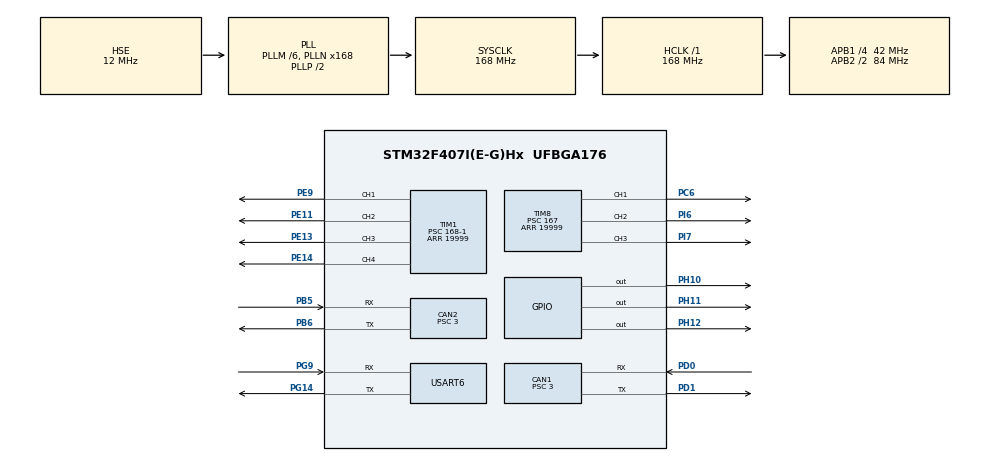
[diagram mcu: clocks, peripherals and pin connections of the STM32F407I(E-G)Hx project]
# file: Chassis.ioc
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CAN1.BS1=CAN_BS1_10TQ
CAN1.BS2=CAN_BS2_3TQ
CAN1.CalculateBaudRate=1000000
CAN1.CalculateTimeBit=1000
CAN1.CalculateTimeQuantum=71.42857142857143
CAN1.Prescaler=3
CAN2.BS1=CAN_BS1_10TQ
CAN2.BS2=CAN_BS2_3TQ
CAN2.CalculateBaudRate=1000000
CAN2.CalculateTimeBit=1000
CAN2.CalculateTimeQuantum=71.42857142857143
CAN2.Prescaler=3
Dma.Request0=USART6_RX
Dma.Request1=USART6_TX
Dma.USART6_RX.0.Direction=DMA_PERIPH_TO_MEMORY
Dma.USART6_RX.0.FIFOMode=DMA_FIFOMODE_DISABLE
Dma.USART6_RX.0.Instance=DMA2_Stream1
Dma.USART6_RX.0.MemDataAlignment=DMA_MDATAALIGN_BYTE
Dma.USART6_RX.0.MemInc=DMA_MINC_ENABLE
Dma.USART6_RX.0.Mode=DMA_NORMAL
Dma.USART6_RX.0.PeriphDataAlignment=DMA_PDATAALIGN_BYTE
Dma.USART6_RX.0.PeriphInc=DMA_PINC_DISABLE
Dma.USART6_RX.0.Priority=DMA_PRIORITY_HIGH
Dma.USART6_TX.1.Direction=DMA_MEMORY_TO_PERIPH
Dma.USART6_TX.1.FIFOMode=DMA_FIFOMODE_DISABLE
Dma.USART6_TX.1.Instance=DMA2_Stream6
Dma.USART6_TX.1.MemDataAlignment=DMA_MDATAALIGN_BYTE
Dma.USART6_TX.1.MemInc=DMA_MINC_ENABLE
Dma.USART6_TX.1.Mode=DMA_NORMAL
Dma.USART6_TX.1.PeriphDataAlignment=DMA_PDATAALIGN_BYTE
Dma.USART6_TX.1.PeriphInc=DMA_PINC_DISABLE
Dma.USART6_TX.1.Priority=DMA_PRIORITY_HIGH
Mcu.Family=STM32F4
Mcu.Name=STM32F407I(E-G)Hx
Mcu.Package=UFBGA176
NVIC.CAN1_RX0_IRQn=true\:0\:0\:false\:false\:true\:true\:true\:true
NVIC.CAN1_TX_IRQn=true\:0\:0\:false\:false\:true\:true\:true\:true
NVIC.CAN2_RX0_IRQn=true\:0\:0\:false\:false\:true\:true\:true\:true
NVIC.CAN2_TX_IRQn=true\:0\:0\:false\:false\:true\:true\:true\:true
NVIC.DMA2_Stream1_IRQn=true\:0\:0\:false\:false\:true\:false\:true\:true
NVIC.DMA2_Stream6_IRQn=true\:0\:0\:false\:false\:true\:false\:true\:true
NVIC.PriorityGroup=NVIC_PRIORITYGROUP_4
NVIC.USART6_IRQn=true\:0\:0\:false\:false\:true\:true\:true\:true
PA13.Mode=Serial_Wire
PA13.Signal=SYS_JTMS-SWDIO
PA14.Mode=Serial_Wire
PA14.Signal=SYS_JTCK-SWCLK
PB5.Mode=CAN_Activate
PB5.Signal=CAN2_RX
PB6.Mode=CAN_Activate
PB6.Signal=CAN2_TX
PC6.Signal=S_TIM8_CH1
PD0.Mode=CAN_Activate
PD0.Signal=CAN1_RX
PD1.Mode=CAN_Activate
PD1.Signal=CAN1_TX
PE11.Signal=S_TIM1_CH2
PE13.Signal=S_TIM1_CH3
PE14.Signal=S_TIM1_CH4
PE9.Signal=S_TIM1_CH1
PG14.Mode=Asynchronous
PG14.Signal=USART6_TX
PG9.Mode=Asynchronous
PG9.Signal=USART6_RX
PH0-OSC_IN.Mode=HSE-External-Oscillator
PH0-OSC_IN.Signal=RCC_OSC_IN
PH1-OSC_OUT.Mode=HSE-External-Oscillator
PH1-OSC_OUT.Signal=RCC_OSC_OUT
PH10.PinState=GPIO_PIN_SET
PH10.Signal=GPIO_Output
PH11.PinState=GPIO_PIN_SET
PH11.Signal=GPIO_Output
PH12.PinState=GPIO_PIN_SET
PH12.Signal=GPIO_Output
PI6.Signal=S_TIM8_CH2
PI7.Signal=S_TIM8_CH3
ProjectManager.HeapSize=0x200
ProjectManager.StackSize=0x400
ProjectManager.TargetToolchain=MDK-ARM V5.32
RCC.48MHZClocksFreq_Value=84000000
RCC.AHBFreq_Value=168000000
RCC.APB1CLKDivider=RCC_HCLK_DIV4
RCC.APB1Freq_Value=42000000
RCC.APB1TimFreq_Value=84000000
RCC.APB2CLKDivider=RCC_HCLK_DIV2
RCC.APB2Freq_Value=84000000
RCC.APB2TimFreq_Value=168000000
RCC.CortexFreq_Value=168000000
RCC.HCLKFreq_Value=168000000
RCC.HSE_VALUE=12000000
RCC.HSI_VALUE=16000000
RCC.LSE_VALUE=32768
RCC.PLLM=6
RCC.PLLN=168
RCC.PLLSourceVirtual=RCC_PLLSOURCE_HSE
RCC.SYSCLKFreq_VALUE=168000000
RCC.SYSCLKSource=RCC_SYSCLKSOURCE_PLLCLK
RCC.VCOOutputFreq_Value=336000000
SH.S_TIM1_CH1.0=TIM1_CH1,PWM Generation1 CH1
SH.S_TIM1_CH2.0=TIM1_CH2,PWM Generation2 CH2
SH.S_TIM1_CH3.0=TIM1_CH3,PWM Generation3 CH3
SH.S_TIM1_CH4.0=TIM1_CH4,PWM Generation4 CH4
SH.S_TIM8_CH1.0=TIM8_CH1,PWM Generation1 CH1
SH.S_TIM8_CH2.0=TIM8_CH2,PWM Generation2 CH2
SH.S_TIM8_CH3.0=TIM8_CH3,PWM Generation3 CH3
STMicroelectronics.X-CUBE-ALGOBUILD.1.4.0.LibraryCcDSPOoLibraryJjDSPOoLibrary=true
STMicroelectronics.X-CUBE-AZRTOS-F4.1.1.0.TX_DISABLE_PREEMPTION_THRESHOLD=1
STMicroelectronics.X-CUBE-AZRTOS-F4.1.1.0.TX_DISABLE_REDUNDANT_CLEARING=1
STMicroelectronics.X-CUBE-AZRTOS-F4.1.1.0.TX_DISABLE_STACK_FILLING=1
STMicroelectronics.X-CUBE-AZRTOS-F4.1.1.0.TX_INLINE_THREAD_RESUME_SUSPEND=1
STMicroelectronics.X-CUBE-AZRTOS-F4.1.1.0.TX_NOT_INTERRUPTABLE=1
STMicroelectronics.X-CUBE-AZRTOS-F4.1.1.0.TX_REACTIVATE_INLINE=1
STMicroelectronics.X-CUBE-AZRTOS-F4.1.1.0.TX_TIMER_PROCESS_IN_ISR=1
STMicroelectronics.X-CUBE-AZRTOS-F4.1.1.0_IsAnAzureRtosMw=true
TIM1.Channel-PWM\ Generation1\ CH1=TIM_CHANNEL_1
TIM1.Channel-PWM\ Generation2\ CH2=TIM_CHANNEL_2
TIM1.Channel-PWM\ Generation3\ CH3=TIM_CHANNEL_3
TIM1.Channel-PWM\ Generation4\ CH4=TIM_CHANNEL_4
TIM1.Period=19999
TIM1.Prescaler=168-1
TIM1.Pulse-PWM\ Generation1\ CH1=0
TIM1.Pulse-PWM\ Generation2\ CH2=0
TIM1.Pulse-PWM\ Generation3\ CH3=0
TIM8.Channel-PWM\ Generation1\ CH1=TIM_CHANNEL_1
TIM8.Channel-PWM\ Generation2\ CH2=TIM_CHANNEL_2
TIM8.Channel-PWM\ Generation3\ CH3=TIM_CHANNEL_3
TIM8.Period=19999
TIM8.Prescaler=167
TIM8.Pulse-PWM\ Generation1\ CH1=0
USART6.VirtualMode=VM_ASYNC
VP_IWDG_VS_IWDG.Mode=IWDG_Activate
VP_STMicroelectronics.X-CUBE-ALGOBUILD_VS_DSPOoLibraryJjLibrary_1.4.0_1.4.0.Mode=DSPOoLibraryJjLibrary
VP_TIM1_VS_ClockSourceINT.Mode=Internal
VP_TIM8_VS_ClockSourceINT.Mode=Internal
board=custom

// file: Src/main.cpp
/* USER CODE BEGIN Header */
/**
  ******************************************************************************
  * @file           : main.c
  * @brief          : Main program body
  ******************************************************************************
  * @attention
  *
  * Copyright (c) 2025 STMicroelectronics.
  * All rights reserved.
  *
  * This software is licensed under terms that can be found in the LICENSE file
  * in the root directory of this software component.
  * If no LICENSE file comes with this software, it is provided AS-IS.
  *
  ******************************************************************************
  */
/* USER CODE END Header */
#include "main.h"

/* USER CODE BEGIN Includes */
#include "bsp.hpp"

#include "DJIMotorHandler.hpp"
#include "ChassisController.hpp"
#include "LED.hpp"
#include "MaixComm.hpp"
#include "SteeringGear.hpp"

#include "stm32f4xx_it.h"
/* USER CODE END Includes */

CAN_HandleTypeDef hcan1;
CAN_HandleTypeDef hcan2;

TIM_HandleTypeDef htim1;
TIM_HandleTypeDef htim8;

UART_HandleTypeDef huart6;
DMA_HandleTypeDef hdma_usart6_rx;
DMA_HandleTypeDef hdma_usart6_tx;

/* USER CODE BEGIN PV */
DJIMotorHandler *DJImotorHandler = DJIMotorHandler::Instance();
ChassisController *chassisController = ChassisController::Instance();
MaixComm *maixcomm = MaixComm::Instance();
SteeringGear *steeringgear = SteeringGear::Instance();
/* USER CODE END PV */

void SystemClock_Config(void);
static void MX_GPIO_Init(void);
static void MX_DMA_Init(void);
static void MX_CAN1_Init(void);
static void MX_CAN2_Init(void);
static void MX_USART6_UART_Init(void);
static void MX_TIM1_Init(void);
static void MX_TIM8_Init(void);
/* USER CODE BEGIN PFP */
void EnableSystickIT(void);
/* USER CODE END PFP */

/* USER CODE BEGIN 0 */

void EnableSystickIT(void)
{
  uint32_t tick_ms = 1; // 1

  HAL_SYSTICK_CLKSourceConfig(SYSTICK_CLKSOURCE_HCLK_DIV8);

  uint32_t reload = SystemCoreClock / 8000 * tick_ms; // SystemCoreClock / 8000 * tick_ms;

  SysTick->CTRL |= SysTick_CTRL_TICKINT_Msk; // Enable SysTick Interrupt
  SysTick->LOAD = reload;
  SysTick->CTRL |= SysTick_CTRL_ENABLE_Msk; // Enable SysTick
}

void SysTick_Handler(void)
{
  /* USER CODE BEGIN SysTick_IRQn 0 */

  /* USER CODE END SysTick_IRQn 0 */
  HAL_IncTick();
  /* USER CODE BEGIN SysTick_IRQn 1 */
  // receive and update data

  // Run control loop
	maixcomm->Update();
  chassisController->Run();
//  steeringgear->SetAngle(45,1);
//  steeringgear->SetAngle(40,3);
  // send data
  DJImotorHandler->sendControlData();

  /* USER CODE END SysTick_IRQn 1 */
}

/* USER CODE END 0 */

int main(void)
{

  /* MCU Configuration--------------------------------------------------------*/

  /* Reset of all peripherals, Initializes the Flash interface and the Systick. */
  HAL_Init();

  /* Configure the system clock */
  SystemClock_Config();

  /* Initialize all configured peripherals */
  MX_GPIO_Init();
  MX_DMA_Init();
  MX_CAN1_Init();
  MX_CAN2_Init();
  MX_USART6_UART_Init();
  MX_TIM1_Init();
  MX_TIM8_Init();
  /* USER CODE BEGIN 2 */
  bsp_init();
	maixcomm->Init();
  chassisController->Init();
  steeringgear->Init();
//	DJImotorHandler->sendControlData();

  EnableSystickIT();
  LED_ALL_ON();
  /* USER CODE END 2 */

  /* Infinite loop */
  while (1)
  {

  }
}

void SystemClock_Config(void)
{
  RCC_OscInitTypeDef RCC_OscInitStruct = {0};
  RCC_ClkInitTypeDef RCC_ClkInitStruct = {0};

  /** Configure the main internal regulator output voltage
  */
  __HAL_RCC_PWR_CLK_ENABLE();
  __HAL_PWR_VOLTAGESCALING_CONFIG(PWR_REGULATOR_VOLTAGE_SCALE1);

  /** Initializes the RCC Oscillators according to the specified parameters
  * in the RCC_OscInitTypeDef structure.
  */
  RCC_OscInitStruct.OscillatorType = RCC_OSCILLATORTYPE_HSE;
  RCC_OscInitStruct.HSEState = RCC_HSE_ON;
  RCC_OscInitStruct.PLL.PLLState = RCC_PLL_ON;
  RCC_OscInitStruct.PLL.PLLSource = RCC_PLLSOURCE_HSE;
  RCC_OscInitStruct.PLL.PLLM = 6;
  RCC_OscInitStruct.PLL.PLLN = 168;
  RCC_OscInitStruct.PLL.PLLP = RCC_PLLP_DIV2;
  RCC_OscInitStruct.PLL.PLLQ = 4;
  if (HAL_RCC_OscConfig(&RCC_OscInitStruct) != HAL_OK)
  {
    Error_Handler();
  }

  /** Initializes the CPU, AHB and APB buses clocks
  */
  RCC_ClkInitStruct.ClockType = RCC_CLOCKTYPE_HCLK|RCC_CLOCKTYPE_SYSCLK
                              |RCC_CLOCKTYPE_PCLK1|RCC_CLOCKTYPE_PCLK2;
  RCC_ClkInitStruct.SYSCLKSource = RCC_SYSCLKSOURCE_PLLCLK;
  RCC_ClkInitStruct.AHBCLKDivider = RCC_SYSCLK_DIV1;
  RCC_ClkInitStruct.APB1CLKDivider = RCC_HCLK_DIV4;
  RCC_ClkInitStruct.APB2CLKDivider = RCC_HCLK_DIV2;

  if (HAL_RCC_ClockConfig(&RCC_ClkInitStruct, FLASH_LATENCY_5) != HAL_OK)
  {
    Error_Handler();
  }
}

static void MX_CAN1_Init(void)
{

  hcan1.Instance = CAN1;
  hcan1.Init.Prescaler = 3;
  hcan1.Init.Mode = CAN_MODE_NORMAL;
  hcan1.Init.SyncJumpWidth = CAN_SJW_1TQ;
  hcan1.Init.TimeSeg1 = CAN_BS1_10TQ;
  hcan1.Init.TimeSeg2 = CAN_BS2_3TQ;
  hcan1.Init.TimeTriggeredMode = DISABLE;
  hcan1.Init.AutoBusOff = DISABLE;
  hcan1.Init.AutoWakeUp = DISABLE;
  hcan1.Init.AutoRetransmission = DISABLE;
  hcan1.Init.ReceiveFifoLocked = DISABLE;
  hcan1.Init.TransmitFifoPriority = DISABLE;
  if (HAL_CAN_Init(&hcan1) != HAL_OK)
  {
    Error_Handler();
  }

}

static void MX_CAN2_Init(void)
{

  hcan2.Instance = CAN2;
  hcan2.Init.Prescaler = 3;
  hcan2.Init.Mode = CAN_MODE_NORMAL;
  hcan2.Init.SyncJumpWidth = CAN_SJW_1TQ;
  hcan2.Init.TimeSeg1 = CAN_BS1_10TQ;
  hcan2.Init.TimeSeg2 = CAN_BS2_3TQ;
  hcan2.Init.TimeTriggeredMode = DISABLE;
  hcan2.Init.AutoBusOff = DISABLE;
  hcan2.Init.AutoWakeUp = DISABLE;
  hcan2.Init.AutoRetransmission = DISABLE;
  hcan2.Init.ReceiveFifoLocked = DISABLE;
  hcan2.Init.TransmitFifoPriority = DISABLE;
  if (HAL_CAN_Init(&hcan2) != HAL_OK)
  {
    Error_Handler();
  }

}

static void MX_TIM1_Init(void)
{

  TIM_ClockConfigTypeDef sClockSourceConfig = {0};
  TIM_MasterConfigTypeDef sMasterConfig = {0};
  TIM_OC_InitTypeDef sConfigOC = {0};
  TIM_BreakDeadTimeConfigTypeDef sBreakDeadTimeConfig = {0};

  htim1.Instance = TIM1;
  htim1.Init.Prescaler = 168-1;
  htim1.Init.CounterMode = TIM_COUNTERMODE_UP;
  htim1.Init.Period = 19999;
  htim1.Init.ClockDivision = TIM_CLOCKDIVISION_DIV1;
  htim1.Init.RepetitionCounter = 0;
  htim1.Init.AutoReloadPreload = TIM_AUTORELOAD_PRELOAD_DISABLE;
  if (HAL_TIM_Base_Init(&htim1) != HAL_OK)
  {
    Error_Handler();
  }
  sClockSourceConfig.ClockSource = TIM_CLOCKSOURCE_INTERNAL;
  if (HAL_TIM_ConfigClockSource(&htim1, &sClockSourceConfig) != HAL_OK)
  {
    Error_Handler();
  }
  if (HAL_TIM_PWM_Init(&htim1) != HAL_OK)
  {
    Error_Handler();
  }
  sMasterConfig.MasterOutputTrigger = TIM_TRGO_RESET;
  sMasterConfig.MasterSlaveMode = TIM_MASTERSLAVEMODE_DISABLE;
  if (HAL_TIMEx_MasterConfigSynchronization(&htim1, &sMasterConfig) != HAL_OK)
  {
    Error_Handler();
  }
  sConfigOC.OCMode = TIM_OCMODE_PWM1;
  sConfigOC.Pulse = 0;
  sConfigOC.OCPolarity = TIM_OCPOLARITY_HIGH;
  sConfigOC.OCNPolarity = TIM_OCNPOLARITY_HIGH;
  sConfigOC.OCFastMode = TIM_OCFAST_DISABLE;
  sConfigOC.OCIdleState = TIM_OCIDLESTATE_RESET;
  sConfigOC.OCNIdleState = TIM_OCNIDLESTATE_RESET;
  if (HAL_TIM_PWM_ConfigChannel(&htim1, &sConfigOC, TIM_CHANNEL_1) != HAL_OK)
  {
    Error_Handler();
  }
  if (HAL_TIM_PWM_ConfigChannel(&htim1, &sConfigOC, TIM_CHANNEL_2) != HAL_OK)
  {
    Error_Handler();
  }
  if (HAL_TIM_PWM_ConfigChannel(&htim1, &sConfigOC, TIM_CHANNEL_3) != HAL_OK)
  {
    Error_Handler();
  }
  if (HAL_TIM_PWM_ConfigChannel(&htim1, &sConfigOC, TIM_CHANNEL_4) != HAL_OK)
  {
    Error_Handler();
  }
  sBreakDeadTimeConfig.OffStateRunMode = TIM_OSSR_DISABLE;
  sBreakDeadTimeConfig.OffStateIDLEMode = TIM_OSSI_DISABLE;
  sBreakDeadTimeConfig.LockLevel = TIM_LOCKLEVEL_OFF;
  sBreakDeadTimeConfig.DeadTime = 0;
  sBreakDeadTimeConfig.BreakState = TIM_BREAK_DISABLE;
  sBreakDeadTimeConfig.BreakPolarity = TIM_BREAKPOLARITY_HIGH;
  sBreakDeadTimeConfig.AutomaticOutput = TIM_AUTOMATICOUTPUT_DISABLE;
  if (HAL_TIMEx_ConfigBreakDeadTime(&htim1, &sBreakDeadTimeConfig) != HAL_OK)
  {
    Error_Handler();
  }
  HAL_TIM_MspPostInit(&htim1);

}

static void MX_TIM8_Init(void)
{

  TIM_ClockConfigTypeDef sClockSourceConfig = {0};
  TIM_MasterConfigTypeDef sMasterConfig = {0};
  TIM_OC_InitTypeDef sConfigOC = {0};
  TIM_BreakDeadTimeConfigTypeDef sBreakDeadTimeConfig = {0};

  htim8.Instance = TIM8;
  htim8.Init.Prescaler = 167;
  htim8.Init.CounterMode = TIM_COUNTERMODE_UP;
  htim8.Init.Period = 19999;
  htim8.Init.ClockDivision = TIM_CLOCKDIVISION_DIV1;
  htim8.Init.RepetitionCounter = 0;
  htim8.Init.AutoReloadPreload = TIM_AUTORELOAD_PRELOAD_DISABLE;
  if (HAL_TIM_Base_Init(&htim8) != HAL_OK)
  {
    Error_Handler();
  }
  sClockSourceConfig.ClockSource = TIM_CLOCKSOURCE_INTERNAL;
  if (HAL_TIM_ConfigClockSource(&htim8, &sClockSourceConfig) != HAL_OK)
  {
    Error_Handler();
  }
  if (HAL_TIM_PWM_Init(&htim8) != HAL_OK)
  {
    Error_Handler();
  }
  sMasterConfig.MasterOutputTrigger = TIM_TRGO_RESET;
  sMasterConfig.MasterSlaveMode = TIM_MASTERSLAVEMODE_DISABLE;
  if (HAL_TIMEx_MasterConfigSynchronization(&htim8, &sMasterConfig) != HAL_OK)
  {
    Error_Handler();
  }
  sConfigOC.OCMode = TIM_OCMODE_PWM1;
  sConfigOC.Pulse = 0;
  sConfigOC.OCPolarity = TIM_OCPOLARITY_HIGH;
  sConfigOC.OCNPolarity = TIM_OCNPOLARITY_HIGH;
  sConfigOC.OCFastMode = TIM_OCFAST_DISABLE;
  sConfigOC.OCIdleState = TIM_OCIDLESTATE_RESET;
  sConfigOC.OCNIdleState = TIM_OCNIDLESTATE_RESET;
  if (HAL_TIM_PWM_ConfigChannel(&htim8, &sConfigOC, TIM_CHANNEL_1) != HAL_OK)
  {
    Error_Handler();
  }
  if (HAL_TIM_PWM_ConfigChannel(&htim8, &sConfigOC, TIM_CHANNEL_2) != HAL_OK)
  {
    Error_Handler();
  }
  if (HAL_TIM_PWM_ConfigChannel(&htim8, &sConfigOC, TIM_CHANNEL_3) != HAL_OK)
  {
    Error_Handler();
  }
  sBreakDeadTimeConfig.OffStateRunMode = TIM_OSSR_DISABLE;
  sBreakDeadTimeConfig.OffStateIDLEMode = TIM_OSSI_DISABLE;
  sBreakDeadTimeConfig.LockLevel = TIM_LOCKLEVEL_OFF;
  sBreakDeadTimeConfig.DeadTime = 0;
  sBreakDeadTimeConfig.BreakState = TIM_BREAK_DISABLE;
  sBreakDeadTimeConfig.BreakPolarity = TIM_BREAKPOLARITY_HIGH;
  sBreakDeadTimeConfig.AutomaticOutput = TIM_AUTOMATICOUTPUT_DISABLE;
  if (HAL_TIMEx_ConfigBreakDeadTime(&htim8, &sBreakDeadTimeConfig) != HAL_OK)
  {
    Error_Handler();
  }
  HAL_TIM_MspPostInit(&htim8);

}

static void MX_USART6_UART_Init(void)
{

  huart6.Instance = USART6;
  huart6.Init.BaudRate = 115200;
  huart6.Init.WordLength = UART_WORDLENGTH_8B;
  huart6.Init.StopBits = UART_STOPBITS_1;
  huart6.Init.Parity = UART_PARITY_NONE;
  huart6.Init.Mode = UART_MODE_TX_RX;
  huart6.Init.HwFlowCtl = UART_HWCONTROL_NONE;
  huart6.Init.OverSampling = UART_OVERSAMPLING_16;
  if (HAL_UART_Init(&huart6) != HAL_OK)
  {
    Error_Handler();
  }

}

static void MX_DMA_Init(void)
{

  /* DMA controller clock enable */
  __HAL_RCC_DMA2_CLK_ENABLE();

  /* DMA interrupt init */
  /* DMA2_Stream1_IRQn interrupt configuration */
  HAL_NVIC_SetPriority(DMA2_Stream1_IRQn, 0, 0);
  HAL_NVIC_EnableIRQ(DMA2_Stream1_IRQn);
  /* DMA2_Stream6_IRQn interrupt configuration */
  HAL_NVIC_SetPriority(DMA2_Stream6_IRQn, 0, 0);
  HAL_NVIC_EnableIRQ(DMA2_Stream6_IRQn);

}

static void MX_GPIO_Init(void)
{
  GPIO_InitTypeDef GPIO_InitStruct = {0};

  /* GPIO Ports Clock Enable */
  __HAL_RCC_GPIOB_CLK_ENABLE();
  __HAL_RCC_GPIOG_CLK_ENABLE();
  __HAL_RCC_GPIOA_CLK_ENABLE();
  __HAL_RCC_GPIOD_CLK_ENABLE();
  __HAL_RCC_GPIOH_CLK_ENABLE();
  __HAL_RCC_GPIOF_CLK_ENABLE();

  /*Configure GPIO pin Output Level */
  HAL_GPIO_WritePin(GPIOH, GPIO_PIN_12|GPIO_PIN_11|GPIO_PIN_10, GPIO_PIN_SET);

  /*Configure GPIO pin : PF6 */
  GPIO_InitStruct.Pin = GPIO_PIN_6;
  GPIO_InitStruct.Mode = GPIO_MODE_AF_PP;
  GPIO_InitStruct.Pull = GPIO_NOPULL;
  GPIO_InitStruct.Speed = GPIO_SPEED_FREQ_LOW;
  GPIO_InitStruct.Alternate = GPIO_AF3_TIM10;
  HAL_GPIO_Init(GPIOF, &GPIO_InitStruct);

  /*Configure GPIO pins : PH12 PH11 PH10 */
  GPIO_InitStruct.Pin = GPIO_PIN_12|GPIO_PIN_11|GPIO_PIN_10;
  GPIO_InitStruct.Mode = GPIO_MODE_OUTPUT_PP;
  GPIO_InitStruct.Pull = GPIO_NOPULL;
  GPIO_InitStruct.Speed = GPIO_SPEED_FREQ_LOW;
  HAL_GPIO_Init(GPIOH, &GPIO_InitStruct);

  /*Configure GPIO pin : PD14 */
  GPIO_InitStruct.Pin = GPIO_PIN_14;
  GPIO_InitStruct.Mode = GPIO_MODE_AF_PP;
  GPIO_InitStruct.Pull = GPIO_NOPULL;
  GPIO_InitStruct.Speed = GPIO_SPEED_FREQ_LOW;
  GPIO_InitStruct.Alternate = GPIO_AF2_TIM4;
  HAL_GPIO_Init(GPIOD, &GPIO_InitStruct);

}

void Error_Handler(void)
{
  __disable_irq();
  while (1)
  {
  }
}
